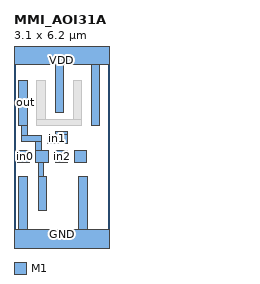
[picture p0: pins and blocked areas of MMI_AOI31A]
MACRO MMI_AOI31A
	CLASS CORE ;
	FOREIGN MMI_AOI31A 0 0 ;
	SIZE 3.1 BY 6.2 ;
	SYMMETRY X Y ;
	SITE CORE1 ;
	PIN out
		DIRECTION output ;
		USE SIGNAL ;
		PORT
			LAYER M1 ;
			RECT 0.16 3.81 0.44 5.28 ;
			LAYER M1 ;
			RECT 0.25 3.465 0.44 3.81 ;
			LAYER M1 ;
			RECT 0.25 3.27 0.895 3.465 ;
			LAYER M1 ;
			RECT 0.7 2.98 0.895 3.27 ;
			LAYER M1 ;
			RECT 0.7 2.6 1.12 2.98 ;
			LAYER M1 ;
			RECT 0.785 2.125 0.975 2.6 ;
			LAYER M1 ;
			RECT 0.785 1.04 1.065 2.125 ;
		END
		AntennaDiffArea 1.09725 ;
	END out
	PIN in1
		DIRECTION input ;
		USE SIGNAL ;
		PORT
			LAYER M1 ;
			RECT 1.36 3.51 1.74 3.6 ;
			LAYER M1 ;
			RECT 1.095 3.23 1.74 3.51 ;
			LAYER M1 ;
			RECT 1.36 3.22 1.74 3.23 ;
		END
		AntennaGateArea 0.40425 ;
	END in1
	PIN GND
		DIRECTION inout ;
		USE GROUND ;
		PORT
			LAYER M1 ;
			RECT 0.155 0.42 0.435 2.125 ;
			LAYER M1 ;
			RECT 2.115 0.42 2.395 2.125 ;
			LAYER M1 ;
			RECT 0 -0.42 3.1 0.42 ;
		END
	END GND
	PIN in2
		DIRECTION input ;
		USE SIGNAL ;
		PORT
			LAYER M1 ;
			RECT 1.36 2.93 1.74 2.98 ;
			LAYER M1 ;
			RECT 1.36 2.65 1.745 2.93 ;
			LAYER M1 ;
			RECT 1.36 2.6 1.74 2.65 ;
		END
		AntennaGateArea 0.40425 ;
	END in2
	PIN VDD
		DIRECTION inout ;
		USE POWER ;
		PORT
			LAYER M1 ;
			RECT 0 5.78 3.1 6.62 ;
			LAYER M1 ;
			RECT 1.34 4.22 1.62 5.78 ;
			LAYER M1 ;
			RECT 2.52 3.81 2.8 5.78 ;
		END
	END VDD
	PIN in3
		DIRECTION input ;
		USE SIGNAL ;
		PORT
			LAYER M1 ;
			RECT 1.98 2.6 2.36 2.98 ;
		END
		AntennaGateArea 0.40425 ;
	END in3
	PIN in0
		DIRECTION input ;
		USE SIGNAL ;
		PORT
			LAYER M1 ;
			RECT 0.12 2.6 0.5 2.98 ;
		END
		AntennaGateArea 0.28875 ;
	END in0
	OBS
		LAYER M1 ;
		RECT 0.75 4 1.03 5.28 ;
		LAYER M1 ;
		RECT 1.93 4 2.21 5.28 ;
		LAYER M1 ;
		RECT 0.75 3.81 2.21 4 ;
	END
END MMI_AOI31A
